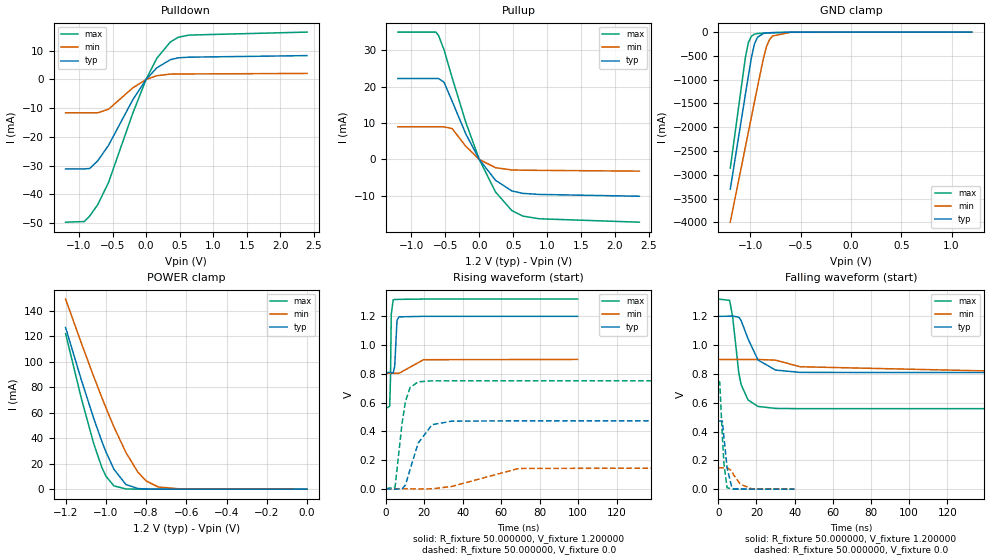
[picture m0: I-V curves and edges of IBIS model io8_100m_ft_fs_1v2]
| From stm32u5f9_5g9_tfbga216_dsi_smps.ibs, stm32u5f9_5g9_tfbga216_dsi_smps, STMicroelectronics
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|   Model io8_100m_ft_fs_1v2
[Model]  io8_100m_ft_fs_1v2
Model_type I/O
Polarity   Non-Inverting
Enable   Active-Low
Vinl =   0.360000V
Vinh =   0.840000V
Vmeas =  0.600000V
Cref =   50.000000pF
Rref =   100.000000M
Vref =   0.0V
C_comp   2.947800pF   2.877700pF   2.996100pF
[Temperature Range]   25.000000   0.140000k   -40.000000
[Pullup Reference]   1.200000V   0.900000V   1.320000V
[Pulldown Reference]   0.0V   0.0V   0.0V
[POWER Clamp Reference]   1.200000V   0.900000V   1.320000V
[GND Clamp Reference]   0.0V   0.0V   0.0V
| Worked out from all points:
|   slope of the pulldown table from 0 to 0.18 V, typ, clamps not added: 40.7 ohm
|   slope of the pullup table from 0 to 0.18 V, typ, clamps not added: 39.5 ohm
|   GND clamp passes 1 mA (typ) near -0.51 V on its own axis
|   POWER clamp passes 1 mA (typ) near -0.86 V on its own axis
|   rising waveform, R_fixture 50.000000, V_fixture 1.200000: 20-80 % time 753ps typ, 2.05ns min, 443ps max; typ from 0.809 V to 1.2 V
|   rising waveform, R_fixture 50.000000, V_fixture 0.0: 20-80 % time 7.25ns typ, 18.3ns min, 3.99ns max; typ from 0 V to 0.473 V
|   falling waveform, R_fixture 50.000000, V_fixture 1.200000: 20-80 % time 7.8ns typ, 18.5ns min, 4.53ns max; typ from 1.2 V to 0.809 V
|   falling waveform, R_fixture 50.000000, V_fixture 0.0: 20-80 % time 2.5ns typ, 4.76ns min, 1.85ns max; typ from 0.473 V to 0 V
[Pulldown]
|Voltage   I(typ)   I(min)   I(max)
-1.2V     -31.16mA   -11.61mA   -49.71mA
-920mV    -31.16mA   -11.61mA   -49.48mA
-840mV    -31mA      -11.61mA   -47.54mA
-720mV    -28.32mA   -11.61mA   -43.58mA
-560mV    -22.95mA   -10.37mA   -35.89mA
-200mV    -7.146mA   -2.964mA   -11.89mA
0V        0A         0A         0A
160mV     4.047mA    1.298mA    7.361mA
360mV     6.87mA     1.87mA     13mA
480mV     7.543mA    1.91mA     14.69mA
640mV     7.764mA    1.923mA    15.46mA
2.4V      8.308mA    2.101mA    16.5mA
[Pullup]
|Voltage   I(typ)   I(min)   I(max)
-1.2V     22.25mA    8.971mA    35.01mA
-640mV    22.25mA    8.971mA    35.01mA
-600mV    22.25mA    8.971mA    34.03mA
-520mV    21.23mA    8.971mA    30.12mA
-400mV    15.99mA    8.489mA    22.45mA
-200mV    7.069mA    3.642mA    10.26mA
0V        550fA      209pA      10fA
240mV     -5.73mA    -2.256mA   -8.953mA
480mV     -8.639mA   -2.877mA   -14.04mA
640mV     -9.31mA    -2.942mA   -15.55mA
880mV     -9.601mA   -2.986mA   -16.29mA
2.36V     -10.1mA    -3.2mA     -17.23mA
[GND_clamp]
|Voltage   I(typ)   I(min)   I(max)
-1.2V     -3.305A    -3.998A    -2.862A
-1.05V    -1.316A    -2.418A    -539.3mA
-1.02V    -921mA     -2.103A    -218.8mA
-990mV    -539.5mA   -1.788A    -87.43mA
-960mV    -252.1mA   -1.474A    -44.36mA
-930mV    -110.5mA   -1.16A     -30.32mA
-870mV    -28.03mA   -549.1mA   -21.09mA
-840mV    -18.43mA   -305.6mA   -18.27mA
-810mV    -13.9mA    -159.7mA   -15.73mA
-780mV    -11.23mA   -82.35mA   -13.37mA
-600mV    -2.976mA   -4.272mA   -3.058mA
1.2V      0A         14.74nA    0A
[POWER_clamp]
|Voltage   I(typ)   I(min)   I(max)
-1.2V     127mA      149.4mA    122.2mA
-1.12V    84.97mA    114mA      70.27mA
-1.06V    55.51mA    88.42mA    35.67mA
-1.02V    37.63mA    72.04mA    17.17mA
-1V       29.51mA    64.13mA    10.3mA
-960mV    15.69mA    48.99mA    2.571mA
-900mV    3.624mA    28.77mA    182.8uA
-840mV    490.7uA    13.24mA    11.35uA
-800mV    116.8uA    6.532mA    1.77uA
-740mV    13.2uA     1.723mA    109.1nA
-620mV    167.3nA    79.35uA    0A
0V        0A         17.84nA    0A
[Ramp]
| variable   typ   min   max
dV/dt_r  0.28375/7.23709n   88.91387m/18.29687n 0.45093/3.98287n
dV/dt_f  0.23460/7.79149n   57.88800m/18.44549n 0.45665/4.52035n
R_load = 50.000000
[Rising Waveform]
R_fixture= 50.000000
V_fixture= 1.200000
V_fixture_min= 0.900000
V_fixture_max= 1.320000
|time   V(typ)   V(min)   V(max)
0s        809mV      803.5mV    558.9mV
2.002ns   809mV      803.5mV    575mV
2.402ns   809.1mV    803.5mV    766.2mV
2.803ns   809mV      803.5mV    1.211V
3.804ns   804.9mV    803.5mV    1.315V
4.605ns   852.3mV    803.5mV    1.317V
5.806ns   1.173V     803.5mV    1.317V
6.807ns   1.196V     803.5mV    1.318V
19.62ns   1.2V       898.1mV    1.32V
99.7ns    1.2V       900mV      1.32V
[Rising Waveform]
R_fixture= 50.000000
V_fixture= 0.0
V_fixture_min= 0.0
V_fixture_max= 0.0
|time   V(typ)   V(min)   V(max)
0s        1.836uV    1.083uV    1.945uV
4.805ns   -2.478mV   913.4nV    12.59mV
8.408ns   -284.1uV   -121.6nV   453.8mV
10.21ns   26.6mV     1.793uV    609.6mV
12.61ns   136mV      48.02uV    704.5mV
16.82ns   318.1mV    -1.253mV   744.3mV
24.02ns   446.1mV    -17.07uV   751.1mV
34.23ns   470.7mV    16.32mV    751.4mV
69.07ns   472.8mV    141.6mV    751.5mV
299.1ns   472.9mV    148.2mV    751.5mV
[Falling Waveform]
R_fixture= 50.000000
V_fixture= 1.200000
V_fixture_min= 0.900000
V_fixture_max= 1.320000
|time   V(typ)   V(min)   V(max)
0s        1.2V       900mV      1.32V
6.006ns   1.201V     900.1mV    1.311V
7.608ns   1.202V     900.6mV    1.191V
10.81ns   1.194V     900.6mV    805mV
12.01ns   1.171V     900.5mV    726.7mV
15.62ns   1.044V     900.4mV    619.4mV
20.82ns   897.2mV    900.5mV    574.5mV
30.03ns   826.8mV    896mV      560.7mV
42.84ns   810.8mV    850mV      559mV
199.4ns   809mV      803.5mV    558.9mV
[Falling Waveform]
R_fixture= 50.000000
V_fixture= 0.0
V_fixture_min= 0.0
V_fixture_max= 0.0
|time   V(typ)   V(min)   V(max)
0s        472.9mV    148.2mV    751.5mV
800.8ps   472.9mV    148.3mV    743.2mV
2.162ns   473.5mV    148.3mV    371.3mV
3.043ns   357.3mV    148.2mV    172.6mV
4.645ns   150mV      148.4mV    10.1mV
6.887ns   23.41mV    129.9mV    1.826mV
8.168ns   2.679mV    97.71mV    920.1uV
11.61ns   1.107mV    34mV       296uV
17.38ns   297.1uV    2.863mV    67.68uV
39.88ns   1.836uV    1.083uV    1.945uV
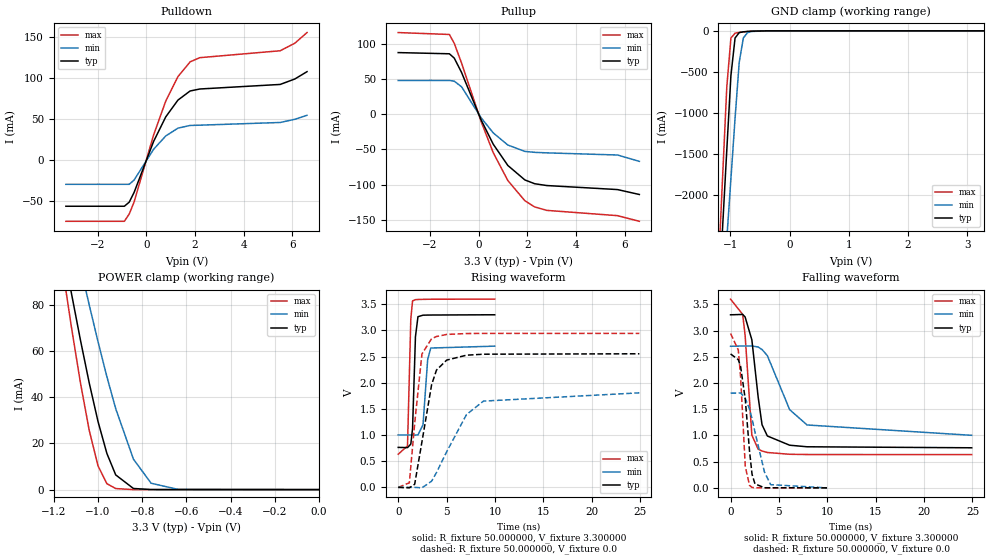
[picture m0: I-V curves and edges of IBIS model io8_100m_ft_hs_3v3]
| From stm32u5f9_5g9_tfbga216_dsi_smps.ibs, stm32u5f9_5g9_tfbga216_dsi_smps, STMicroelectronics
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|   Model io8_100m_ft_hs_3v3
[Model]  io8_100m_ft_hs_3v3
Model_type I/O
Polarity   Non-Inverting
Enable   Active-Low
Vinl =   0.990000V
Vinh =   2.310000V
Vmeas =  1.650000V
Cref =   50.000000pF
Rref =   100.000000M
Vref =   0.0V
C_comp   3.313100pF   3.281800pF   3.354500pF
[Temperature Range]   25.000000   0.140000k   -40.000000
[Pullup Reference]   3.300000V   2.700000V   3.600000V
[Pulldown Reference]   0.0V   0.0V   0.0V
[POWER Clamp Reference]   3.300000V   2.700000V   3.600000V
[GND Clamp Reference]   0.0V   0.0V   0.0V
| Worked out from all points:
|   slope of the pulldown table from 0 to 0.495 V, typ, clamps not added: 14 ohm
|   slope of the pullup table from 0 to 0.495 V, typ, clamps not added: 13.7 ohm
|   GND clamp passes 1 mA (typ) near -0.51 V on its own axis
|   POWER clamp passes 1 mA (typ) near -0.85 V on its own axis
|   rising waveform, R_fixture 50.000000, V_fixture 3.300000: 20-80 % time 245ps typ, 342ps min, 208ps max; typ from 0.764 V to 3.3 V
|   rising waveform, R_fixture 50.000000, V_fixture 0.0: 20-80 % time 1.41ns typ, 3.1ns min, 872ps max; typ from 0 V to 2.55 V
|   falling waveform, R_fixture 50.000000, V_fixture 3.300000: 20-80 % time 959ps typ, 2.51ns min, 626ps max; typ from 3.3 V to 0.764 V
|   falling waveform, R_fixture 50.000000, V_fixture 0.0: 20-80 % time 727ps typ, 1.36ns min, 504ps max; typ from 2.55 V to 0 V
[Pulldown]
|Voltage   I(typ)   I(min)   I(max)
-3.3V     -56.06mA   -29.42mA   -74.35mA
-900mV    -56.06mA   -29.42mA   -74.35mA
-700mV    -51.09mA   -29.42mA   -65.48mA
-500mV    -39.32mA   -24.2mA    -50.88mA
300mV     22.62mA    13.13mA    30.43mA
800mV     52.54mA    29.36mA    71.75mA
1.3V      72.91mA    38.82mA    101.4mA
1.8V      84.02mA    42.13mA    119.4mA
2.2V      86.43mA    42.46mA    124.5mA
5.5V      91.98mA    45.75mA    132.9mA
6.1V      98.6mA     49.6mA     142.1mA
6.6V      107.5mA    54.5mA     155mA
[Pullup]
|Voltage   I(typ)   I(min)   I(max)
-3.3V     87.21mA    47.72mA    115.6mA
-1.2V     85.52mA    47.72mA    112.9mA
-1V       79.41mA    46.66mA    100.4mA
-700mV    59.08mA    38.76mA    72.42mA
100mV     -8.009mA   -5.102mA   -10.2mA
600mV     -42.64mA   -26.6mA    -54.61mA
1.2V      -72.81mA   -43.84mA   -94.18mA
1.9V      -93.37mA   -52.9mA    -122.9mA
2.3V      -98.71mA   -54.23mA   -131.6mA
2.8V      -101.3mA   -54.97mA   -136.5mA
5.7V      -107mA     -58mA      -144mA
6.6V      -114mA     -67mA      -152mA
[GND_clamp]
|Voltage   I(typ)   I(min)   I(max)
-3.3V     -9.848A    -9.957A    -9.458A
-1.2V     -3.312A    -4.013A    -2.863A
-1.13V    -2.381A    -3.274A    -1.769A
-1.06V    -1.452A    -2.535A    -684.7mA
-990mV    -542.9mA   -1.798A    -88.02mA
-920mV    -87.11mA   -1.064A    -28.44mA
-850mV    -22.1mA    -382.4mA   -19.61mA
-780mV    -11.97mA   -86.98mA   -13.71mA
-710mV    -7.619mA   -22.26mA   -8.745mA
-640mV    -4.493mA   -7.773mA   -4.817mA
-360mV    -31.22uA   -172.6uA   -8.607uA
3.28V     0A         15.66nA    -5.841nA
[POWER_clamp]
|Voltage   I(typ)   I(min)   I(max)
-3.28V    1.355A     1.167A     1.664A
-1.16V    105.7mA    131.6mA    95.69mA
-1.12V    84.97mA    114mA      70.27mA
-1.08V    65.05mA    96.83mA    46.54mA
-1.04V    46.34mA    80.15mA    25.76mA
-1V       29.51mA    64.13mA    10.3mA
-960mV    15.69mA    48.99mA    2.571mA
-920mV    6.373mA    35.1mA     455.6uA
-840mV    490.7uA    13.24mA    11.36uA
-760mV    27.33uA    2.767mA    276.6nA
-640mV    346.6nA    134.1uA    15.62nA
0V        0A         19.91nA    0A
[Ramp]
| variable   typ   min   max
dV/dt_r  1.53252/1.41104n   1.08420/3.09938n   1.76664/0.87063n
dV/dt_f  1.52149/0.95635n   1.01802/2.50554n   1.77964/0.62432n
R_load = 50.000000
[Rising Waveform]
R_fixture= 50.000000
V_fixture= 3.300000
V_fixture_min= 2.700000
V_fixture_max= 3.600000
|time   V(typ)   V(min)   V(max)
0s        764.2mV    1.002V     633.9mV
961ps     760mV      1.002V     794mV
1.301ns   826.9mV    1.002V     3.216V
1.481ns   1.121V     1.002V     3.565V
1.782ns   2.884V     999.4mV    3.589V
2.042ns   3.263V     1.002V     3.592V
2.563ns   3.292V     1.198V     3.595V
3.043ns   3.294V     2.444V     3.596V
3.363ns   3.295V     2.664V     3.597V
9.97ns    3.3V       2.7V       3.599V
[Rising Waveform]
R_fixture= 50.000000
V_fixture= 0.0
V_fixture_min= 0.0
V_fixture_max= 0.0
|time   V(typ)   V(min)   V(max)
0s        6.7uV      6.794uV    3.582uV
1.151ns   -8.749mV   18.83uV    86.4mV
1.702ns   59.79mV    -904.3nV   1.225V
2.452ns   870.8mV    -9.576mV   2.551V
3.453ns   1.964V     118.8mV    2.843V
3.954ns   2.242V     282.3mV    2.884V
5.005ns   2.433V     679.4mV    2.924V
7.057ns   2.527V     1.392V     2.941V
8.809ns   2.546V     1.649V     2.944V
24.92ns   2.554V     1.807V     2.944V
[Falling Waveform]
R_fixture= 50.000000
V_fixture= 3.300000
V_fixture_min= 2.700000
V_fixture_max= 3.600000
|time   V(typ)   V(min)   V(max)
0s        3.3V       2.7V       3.599V
1.251ns   3.307V     2.705V     3.308V
1.502ns   3.26V      2.706V     2.919V
2.202ns   2.823V     2.706V     1.005V
2.853ns   1.732V     2.686V     738.5mV
3.253ns   1.204V     2.638V     702.6mV
3.804ns   989.2mV    2.522V     674.6mV
6.106ns   813.3mV    1.492V     640.4mV
7.908ns   783.5mV    1.199V     635.9mV
24.92ns   764.2mV    1.002V     633.9mV
[Falling Waveform]
R_fixture= 50.000000
V_fixture= 0.0
V_fixture_min= 0.0
V_fixture_max= 0.0
|time   V(typ)   V(min)   V(max)
0s        2.554V     1.807V     2.944V
800.8ps   2.444V     1.807V     2.63V
1.041ns   2.315V     1.811V     2.115V
1.522ns   1.687V     1.707V     408.1mV
1.962ns   699.7mV    1.505V     46.54mV
2.222ns   257.8mV    1.317V     7.735mV
2.523ns   75.89mV    1.064V     3.104mV
3.504ns   2.52mV     303mV      1.393mV
4.144ns   1.613mV    60.78mV    1.06mV
9.97ns    6.7uV      6.794uV    3.582uV
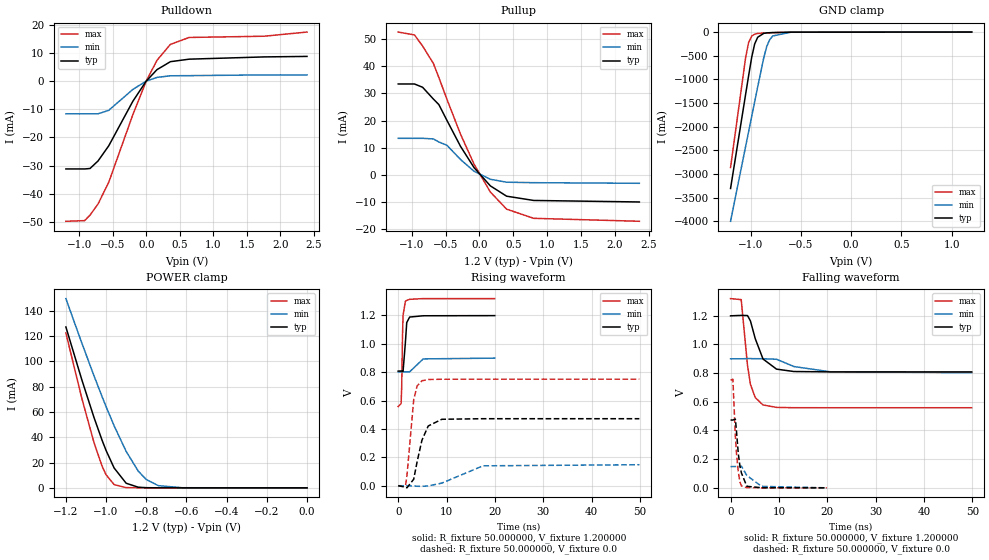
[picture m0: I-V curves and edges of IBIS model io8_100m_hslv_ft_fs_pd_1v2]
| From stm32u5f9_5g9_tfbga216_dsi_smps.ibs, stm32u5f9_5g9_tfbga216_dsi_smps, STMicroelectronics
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|   Model io8_100m_hslv_ft_fs_pd_1v2
[Model]  io8_100m_hslv_ft_fs_pd_1v2
Model_type I/O
Polarity   Non-Inverting
Enable   Active-Low
Vinl =   0.360000V
Vinh =   0.840000V
Vmeas =  0.600000V
Cref =   50.000000pF
Rref =   100.000000M
Vref =   0.0V
C_comp   3.030100pF   2.960800pF   3.078300pF
[Temperature Range]   25.000000   0.140000k   -40.000000
[Pullup Reference]   1.200000V   0.900000V   1.320000V
[Pulldown Reference]   0.0V   0.0V   0.0V
[POWER Clamp Reference]   1.200000V   0.900000V   1.320000V
[GND Clamp Reference]   0.0V   0.0V   0.0V
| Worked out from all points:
|   slope of the pulldown table from 0 to 0.18 V, typ, clamps not added: 40.7 ohm
|   slope of the pullup table from 0 to 0.18 V, typ, clamps not added: 39.5 ohm
|   GND clamp passes 1 mA (typ) near -0.51 V on its own axis
|   POWER clamp passes 1 mA (typ) near -0.86 V on its own axis
|   rising waveform, R_fixture 50.000000, V_fixture 1.200000: 20-80 % time 362ps typ, 843ps min, 238ps max; typ from 0.808 V to 1.2 V
|   rising waveform, R_fixture 50.000000, V_fixture 0.0: 20-80 % time 2ns typ, 4.56ns min, 1.18ns max; typ from 0 V to 0.472 V
|   falling waveform, R_fixture 50.000000, V_fixture 1.200000: 20-80 % time 2.46ns typ, 5.4ns min, 1.5ns max; typ from 1.2 V to 0.808 V
|   falling waveform, R_fixture 50.000000, V_fixture 0.0: 20-80 % time 1.05ns typ, 1.99ns min, 804ps max; typ from 0.472 V to 0 V
[Pulldown]
|Voltage   I(typ)   I(min)   I(max)
-1.2V     -31.16mA   -11.61mA   -49.71mA
-920mV    -31.16mA   -11.61mA   -49.48mA
-840mV    -31mA      -11.61mA   -47.54mA
-720mV    -28.33mA   -11.61mA   -43.58mA
-560mV    -22.95mA   -10.37mA   -35.89mA
-200mV    -7.146mA   -2.964mA   -11.89mA
0V        0A         -1pA       0A
160mV     4.047mA    1.298mA    7.361mA
360mV     6.87mA     1.87mA     13mA
640mV     7.765mA    1.923mA    15.46mA
1.76V     8.564mA    2.187mA    15.9mA
2.4V      8.742mA    2.187mA    17.38mA
[Pullup]
|Voltage   I(typ)   I(min)   I(max)
-1.2V     33.49mA    13.42mA    52.68mA
-960mV    33.49mA    13.42mA    51.61mA
-840mV    32.28mA    13.42mA    47.51mA
-680mV    27.9mA     13.19mA    41.05mA
-600mV    25.88mA    12.07mA    35.87mA
-480mV    20.01mA    10.83mA    27.79mA
-280mV    10.44mA    5.592mA    14.93mA
-80mV     2.58mA     1.232mA    3.849mA
160mV     -4.145mA   -1.713mA   -6.415mA
400mV     -7.962mA   -2.792mA   -12.75mA
800mV     -9.537mA   -2.973mA   -16.14mA
2.36V     -10.1mA    -3.2mA     -17.23mA
[GND_clamp]
|Voltage   I(typ)   I(min)   I(max)
-1.2V     -3.305A    -3.998A    -2.862A
-1.05V    -1.316A    -2.418A    -539.3mA
-1.02V    -921mA     -2.103A    -218.8mA
-990mV    -539.5mA   -1.788A    -87.45mA
-960mV    -252.2mA   -1.474A    -44.37mA
-930mV    -110.5mA   -1.16A     -30.33mA
-870mV    -28.04mA   -549.1mA   -21.1mA
-840mV    -18.44mA   -305.6mA   -18.29mA
-810mV    -13.92mA   -159.7mA   -15.75mA
-780mV    -11.24mA   -82.36mA   -13.39mA
-600mV    -2.986mA   -4.279mA   -3.072mA
1.2V      30.28uA    18.17uA    37.27uA
[POWER_clamp]
|Voltage   I(typ)   I(min)   I(max)
-1.2V     127mA      149.4mA    122.2mA
-1.12V    84.97mA    114mA      70.27mA
-1.06V    55.51mA    88.42mA    35.67mA
-1.02V    37.63mA    72.04mA    17.17mA
-1V       29.51mA    64.13mA    10.3mA
-960mV    15.69mA    48.99mA    2.571mA
-900mV    3.624mA    28.77mA    182.8uA
-840mV    490.7uA    13.24mA    11.35uA
-800mV    116.8uA    6.532mA    1.77uA
-740mV    13.2uA     1.723mA    109.1nA
-620mV    167.3nA    79.35uA    0A
0V        0A         17.84nA    0A
[Ramp]
| variable   typ   min   max
dV/dt_r  0.28340/1.99687n   88.81788m/4.55262n  0.45044/1.18302n
dV/dt_f  0.23486/2.45404n   58.02600m/5.39175n  0.45673/1.50145n
R_load = 50.000000
[Rising Waveform]
R_fixture= 50.000000
V_fixture= 1.200000
V_fixture_min= 0.900000
V_fixture_max= 1.320000
|time   V(typ)   V(min)   V(max)
0s        808mV      802.7mV    558.3mV
600.6ps   808.7mV    802.7mV    579.2mV
720.7ps   808.6mV    802.7mV    698.5mV
880.9ps   807.1mV    802.7mV    1.046V
1.001ns   805.7mV    802.7mV    1.2V
1.481ns   1.009V     802.8mV    1.3V
1.762ns   1.15V      802.9mV    1.306V
2.362ns   1.189V     802.9mV    1.314V
5.165ns   1.198V     893.9mV    1.319V
19.94ns   1.199V     899.4mV    1.319V
[Rising Waveform]
R_fixture= 50.000000
V_fixture= 0.0
V_fixture_min= 0.0
V_fixture_max= 0.0
|time   V(typ)   V(min)   V(max)
0s        -14.66uV   -6.095uV   -48.72uV
1.502ns   -10.14mV   -40.81uV   -1.013mV
1.802ns   -14.87mV   -38.25uV   69.37mV
3.203ns   45.81mV    -1.916mV   606.2mV
3.904ns   168.6mV    -3.803mV   703mV
4.905ns   320.8mV    -4.272mV   740mV
6.206ns   421.2mV    -1.571mV   748.8mV
9.009ns   468.4mV    18.4mV     750.7mV
17.52ns   472.4mV    140.2mV    750.9mV
49.85ns   472.4mV    148.1mV    750.9mV
[Falling Waveform]
R_fixture= 50.000000
V_fixture= 1.200000
V_fixture_min= 0.900000
V_fixture_max= 1.320000
|time   V(typ)   V(min)   V(max)
0s        1.199V     899.4mV    1.319V
2.202ns   1.202V     899.1mV    1.312V
3.504ns   1.201V     901.4mV    854.4mV
4.104ns   1.164V     900.9mV    721.7mV
5.105ns   1.04V      900.1mV    629.1mV
6.707ns   898.1mV    899.9mV    577.7mV
9.51ns    827.3mV    896.3mV    560.7mV
13.11ns   810.7mV    845.4mV    558.5mV
20.62ns   808.1mV    808.8mV    558.3mV
49.85ns   808mV      802.7mV    558.3mV
[Falling Waveform]
R_fixture= 50.000000
V_fixture= 0.0
V_fixture_min= 0.0
V_fixture_max= 0.0
|time   V(typ)   V(min)   V(max)
0s        472.4mV    148.1mV    750.9mV
480.5ps   472.6mV    148.2mV    756.6mV
1.001ns   478.8mV    148.2mV    357.1mV
1.241ns   388.5mV    148.2mV    234.3mV
1.602ns   237.5mV    148.1mV    114mV
1.922ns   156.2mV    148.4mV    42.56mV
2.242ns   104.2mV    151.4mV    12.92mV
3.363ns   10.66mV    86.08mV    1.68mV
6.406ns   686.2uV    10.19mV    72.86uV
19.94ns   -14.66uV   -6.095uV   -48.72uV
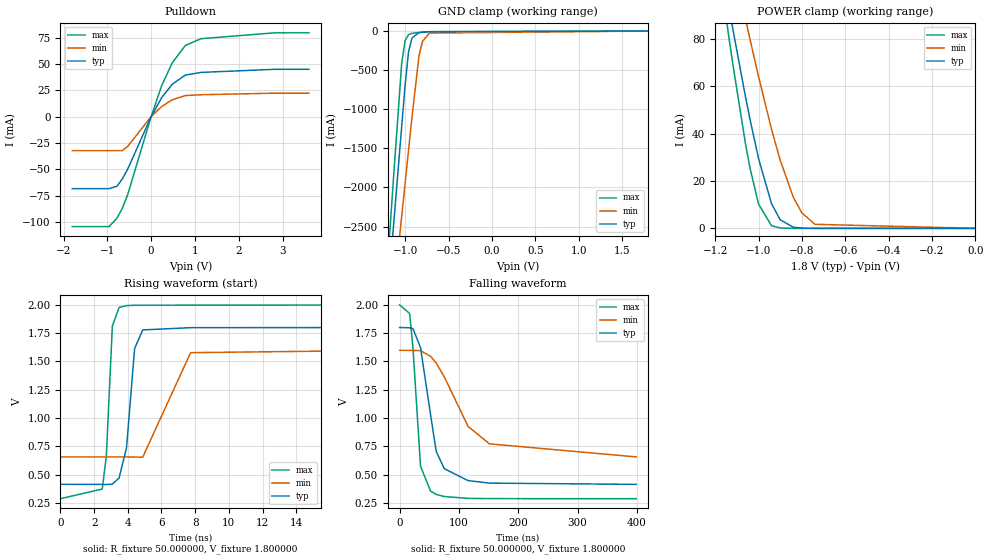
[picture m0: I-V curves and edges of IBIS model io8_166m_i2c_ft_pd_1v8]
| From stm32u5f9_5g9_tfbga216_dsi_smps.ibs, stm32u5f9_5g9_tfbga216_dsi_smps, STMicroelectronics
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|   Model io8_166m_i2c_ft_pd_1v8
[Model]  io8_166m_i2c_ft_pd_1v8
Model_type I/O_open_drain
Polarity   Non-Inverting
Enable   Active-Low
Vinl =   0.540000V
Vinh =   1.260000V
Vmeas =  0.800000V
Cref =   50.000000pF
Rref =   10.000000
Vref =   0.900000V
C_comp   3.364500pF   3.359200pF   3.406800pF
[Temperature Range]   25.000000   0.140000k   -40.000000
[Pullup Reference]   1.800000V   1.600000V   2.000000V
[Pulldown Reference]   0.0V   0.0V   0.0V
[POWER Clamp Reference]   1.800000V   1.600000V   2.000000V
[GND Clamp Reference]   0.0V   0.0V   0.0V
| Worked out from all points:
|   slope of the pulldown table from 0 to 0.27 V, typ, clamps not added: 13.6 ohm
|   GND clamp passes 1 mA (typ) near -0.50 V on its own axis
|   POWER clamp passes 1 mA (typ) near -0.86 V on its own axis
|   rising waveform, R_fixture 50.000000, V_fixture 1.800000: 20-80 % time 442ps typ, 899ps min, 293ps max; typ from 0.414 V to 1.8 V
|   falling waveform, R_fixture 50.000000, V_fixture 1.800000: 20-80 % time 23.4ns typ, 59.2ns min, 12.2ns max; typ from 1.8 V to 0.414 V
[Pulldown]
|Voltage   I(typ)   I(min)   I(max)
-1.8V     -68.38mA   -32.32mA   -104.4mA
-960mV    -68.38mA   -32.32mA   -104.4mA
-780mV    -66.08mA   -32.32mA   -96.43mA
-660mV    -59.2mA    -32.31mA   -87.22mA
-540mV    -50.22mA   -28.51mA   -74.66mA
0V        -10fA      -200fA     0A
240mV     18.04mA    9.6mA      29.42mA
480mV     30.68mA    16.02mA    50.95mA
780mV     39.48mA    19.99mA    67.56mA
1.14V     41.99mA    20.78mA    74.01mA
2.82V     44.93mA    22.28mA    79.57mA
3.6V      44.93mA    22.28mA    79.57mA
[GND_clamp]
|Voltage   I(typ)   I(min)   I(max)
-1.8V     -9.908A    -9.683A    -9.994A
-1.2V     -3.383A    -4.084A    -2.934A
-1.16V    -2.841A    -3.655A    -2.294A
-1.12V    -2.299A    -3.226A    -1.656A
-1.04V    -1.218A    -2.369A    -414.2mA
-1V       -684.7mA   -1.941A    -119.2mA
-960mV    -257.2mA   -1.514A    -45.67mA
-920mV    -87.04mA   -1.089A    -28.94mA
-840mV    -19.36mA   -312.8mA   -18.98mA
-800mV    -13.56mA   -132.4mA   -15.51mA
-720mV    -8.053mA   -25.67mA   -9.505mA
1.8V      45.71uA    33.32uA    56.11uA
[POWER_clamp]
|Voltage   I(typ)   I(min)   I(max)
-1.8V     470.8mA    433.7mA    554.6mA
-1.14V    95.25mA    122.7mA    82.82mA
-1.12V    84.97mA    114mA      70.27mA
-1.06V    55.51mA    88.42mA    35.67mA
-1.04V    46.34mA    80.15mA    25.76mA
-1V       29.51mA    64.13mA    10.3mA
-940mV    10.39mA    41.86mA    1.109mA
-900mV    3.624mA    28.77mA    182.8uA
-840mV    490.7uA    13.24mA    11.35uA
-800mV    116.8uA    6.532mA    1.77uA
-740mV    13.2uA     1.724mA    109.3nA
0V        0A         18.75nA    0A
[Ramp]
| variable   typ   min   max
dV/dt_r  0.83119/0.44455n   0.56525/0.89877n   1.02738/0.29256n
dV/dt_f  0.83143/23.37507n   0.56491/59.21208n   1.02744/12.19581n
R_load = 50.000000
[Rising Waveform]
R_fixture= 50.000000
V_fixture= 1.800000
V_fixture_min= 1.600000
V_fixture_max= 2.000000
|time   V(typ)   V(min)   V(max)
0s        413.8mV    656.4mV    287.1mV
2.482ns   413.5mV    656.4mV    372.3mV
2.723ns   412.6mV    656.4mV    660.2mV
3.083ns   416.1mV    656.4mV    1.814V
3.483ns   470.5mV    656.4mV    1.978V
3.924ns   738.4mV    656.3mV    1.994V
4.404ns   1.614V     655.3mV    1.997V
4.885ns   1.779V     653.9mV    1.997V
7.728ns   1.799V     1.578V     1.998V
19.94ns   1.8V       1.599V     2V
[Falling Waveform]
R_fixture= 50.000000
V_fixture= 1.800000
V_fixture_min= 1.600000
V_fixture_max= 2.000000
|time   V(typ)   V(min)   V(max)
0s        1.8V       1.599V     2V
16.82ns   1.798V     1.598V     1.925V
22.42ns   1.791V     1.598V     1.623V
35.24ns   1.622V     1.595V     574.5mV
52.05ns   1.032V     1.546V     353.8mV
61.66ns   704.5mV    1.486V     325mV
75.28ns   552.5mV    1.364V     306.1mV
115.3ns   446.9mV    926.3mV    290mV
151.4ns   424.8mV    772mV      287.7mV
398.8ns   413.8mV    656.4mV    287.1mV
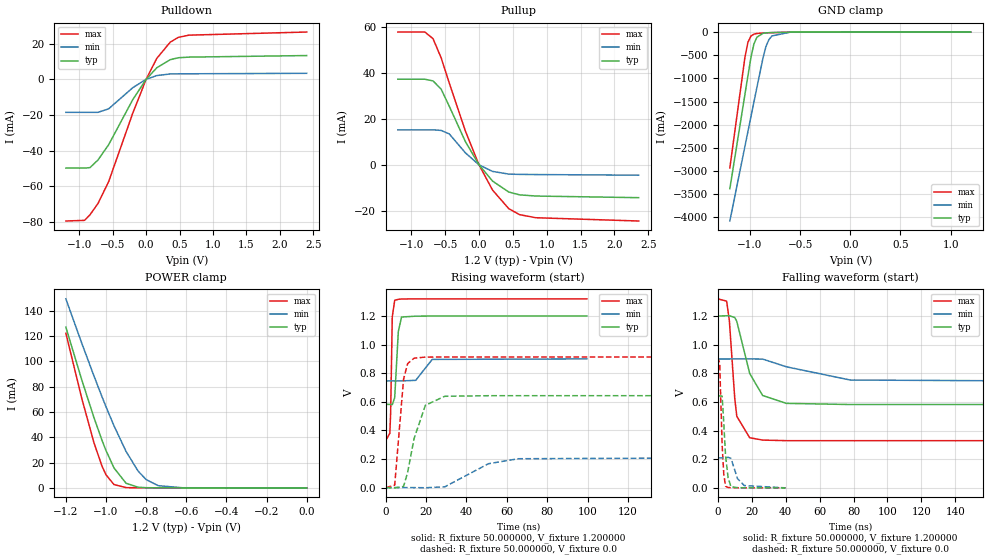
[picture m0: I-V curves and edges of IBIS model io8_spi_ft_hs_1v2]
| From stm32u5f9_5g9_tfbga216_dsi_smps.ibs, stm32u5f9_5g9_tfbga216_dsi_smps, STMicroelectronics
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|   Model io8_spi_ft_hs_1v2
[Model]  io8_spi_ft_hs_1v2
Model_type I/O
Polarity   Non-Inverting
Enable   Active-Low
Vinl =   0.360000V
Vinh =   0.840000V
Vmeas =  0.600000V
Cref =   50.000000pF
Rref =   100.000000M
Vref =   0.0V
C_comp   3.132800pF   3.069700pF   3.178000pF
[Temperature Range]   25.000000   0.140000k   -40.000000
[Pullup Reference]   1.200000V   0.900000V   1.320000V
[Pulldown Reference]   0.0V   0.0V   0.0V
[POWER Clamp Reference]   1.200000V   0.900000V   1.320000V
[GND Clamp Reference]   0.0V   0.0V   0.0V
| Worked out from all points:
|   slope of the pulldown table from 0 to 0.18 V, typ, clamps not added: 25.4 ohm
|   slope of the pullup table from 0 to 0.18 V, typ, clamps not added: 27.8 ohm
|   GND clamp passes 1 mA (typ) near -0.51 V on its own axis
|   POWER clamp passes 1 mA (typ) near -0.86 V on its own axis
|   rising waveform, R_fixture 50.000000, V_fixture 1.200000: 20-80 % time 1.31ns typ, 3.47ns min, 671ps max; typ from 0.582 V to 1.2 V
|   rising waveform, R_fixture 50.000000, V_fixture 0.0: 20-80 % time 6.24ns typ, 16ns min, 3.02ns max; typ from 0 V to 0.643 V
|   falling waveform, R_fixture 50.000000, V_fixture 1.200000: 20-80 % time 8.69ns typ, 20.8ns min, 3.7ns max; typ from 1.2 V to 0.582 V
|   falling waveform, R_fixture 50.000000, V_fixture 0.0: 20-80 % time 2.1ns typ, 4.02ns min, 1.52ns max; typ from 0.643 V to 0 V
[Pulldown]
|Voltage   I(typ)   I(min)   I(max)
-1.2V     -49.85mA   -18.57mA   -79.56mA
-920mV    -49.85mA   -18.57mA   -79.19mA
-840mV    -49.59mA   -18.57mA   -76.08mA
-720mV    -45.32mA   -18.57mA   -69.74mA
-560mV    -36.71mA   -16.58mA   -57.44mA
-200mV    -11.43mA   -4.74mA    -19.03mA
0V        0A         -600fA     0A
160mV     6.476mA    2.075mA    11.78mA
360mV     10.99mA    2.989mA    20.81mA
480mV     12.07mA    3.053mA    23.52mA
640mV     12.43mA    3.074mA    24.76mA
2.4V      13.31mA    3.34mA     26.51mA
[Pullup]
|Voltage   I(typ)   I(min)   I(max)
-1.2V     37.31mA    15.26mA    57.88mA
-800mV    37.31mA    15.26mA    57.88mA
-680mV    36.58mA    15.26mA    54.98mA
-560mV    33mA       15mA       46.63mA
-440mV    25.52mA    13.49mA    35.67mA
-200mV    10.05mA    5.175mA    14.59mA
0V        580fA      233pA      0A
200mV     -7.072mA   -2.852mA   -11mA
440mV     -11.84mA   -4.03mA    -19.1mA
600mV     -13.07mA   -4.154mA   -21.71mA
840mV     -13.59mA   -4.223mA   -23.04mA
2.36V     -14.3mA    -4.5mA     -24.47mA
[GND_clamp]
|Voltage   I(typ)   I(min)   I(max)
-1.2V     -3.379A    -4.076A    -2.932A
-1.05V    -1.35A     -2.47A     -550.7mA
-1.02V    -947.8mA   -2.149A    -221.5mA
-990mV    -552.4mA   -1.829A    -88.44mA
-960mV    -255.3mA   -1.51A     -44.87mA
-930mV    -111.8mA   -1.191A    -30.68mA
-870mV    -28.35mA   -564.6mA   -21.34mA
-840mV    -18.65mA   -309.5mA   -18.49mA
-810mV    -14.07mA   -161.6mA   -15.92mA
-780mV    -11.37mA   -83.33mA   -13.53mA
-600mV    -3.009mA   -4.321mA   -3.091mA
1.2V      0A         13.65nA    0A
[POWER_clamp]
|Voltage   I(typ)   I(min)   I(max)
-1.2V     127mA      149.4mA    122.2mA
-1.12V    84.97mA    114mA      70.27mA
-1.06V    55.51mA    88.42mA    35.67mA
-1.02V    37.63mA    72.04mA    17.17mA
-1V       29.51mA    64.13mA    10.3mA
-960mV    15.69mA    48.99mA    2.571mA
-900mV    3.624mA    28.77mA    182.8uA
-840mV    490.7uA    13.24mA    11.35uA
-800mV    116.8uA    6.532mA    1.77uA
-740mV    13.2uA     1.724mA    109.1nA
-620mV    167.4nA    79.36uA    0A
0V        0A         17.87nA    0A
[Ramp]
| variable   typ   min   max
dV/dt_r  0.38564/6.23137n   0.12553/15.91315n   0.54826/3.00577n
dV/dt_f  0.37078/8.68374n   92.42400m/20.74691n 0.59435/3.69688n
R_load = 50.000000
[Rising Waveform]
R_fixture= 50.000000
V_fixture= 1.200000
V_fixture_min= 0.900000
V_fixture_max= 1.320000
|time   V(typ)   V(min)   V(max)
0s        582mV      745.9mV    329.4mV
2.002ns   582.1mV    745.9mV    380.1mV
2.402ns   582mV      745.9mV    525.4mV
3.203ns   580mV      745.9mV    1.194V
4.404ns   629mV      745.9mV    1.31V
6.206ns   1.092V     745.9mV    1.317V
7.808ns   1.193V     746mV      1.319V
14.81ns   1.199V     750.1mV    1.32V
23.02ns   1.2V       896.6mV    1.32V
99.7ns    1.2V       900mV      1.32V
[Rising Waveform]
R_fixture= 50.000000
V_fixture= 0.0
V_fixture_min= 0.0
V_fixture_max= 0.0
|time   V(typ)   V(min)   V(max)
0s        1.319uV    949.7nV    109.5nV
4.404ns   -1.865mV   785.3nV    16.67mV
8.809ns   8.008mV    -251nV     759mV
10.81ns   106mV      8.805uV    866.9mV
14.01ns   342.6mV    -142uV     905.1mV
19.62ns   575.8mV    -1.182mV   912.8mV
29.23ns   638.6mV    5.363mV    913.4mV
50.85ns   642.6mV    166.8mV    913.5mV
65.67ns   642.7mV    201.8mV    913.5mV
199.4ns   642.8mV    209.3mV    913.5mV
[Falling Waveform]
R_fixture= 50.000000
V_fixture= 1.200000
V_fixture_min= 0.900000
V_fixture_max= 1.320000
|time   V(typ)   V(min)   V(max)
0s        1.2V       900mV      1.32V
5.205ns   1.202V     899.9mV    1.304V
6.807ns   1.202V     900mV      1.169V
10.01ns   1.19V      901.1mV    621.9mV
11.21ns   1.162V     901.1mV    499.9mV
18.82ns   798.4mV    900.6mV    349.9mV
26.43ns   645.1mV    899.5mV    333.6mV
40.44ns   590mV      845.4mV    329.6mV
78.08ns   582mV      753.1mV    329.4mV
199.4ns   582mV      745.9mV    329.4mV
[Falling Waveform]
R_fixture= 50.000000
V_fixture= 0.0
V_fixture_min= 0.0
V_fixture_max= 0.0
|time   V(typ)   V(min)   V(max)
0s        642.8mV    209.3mV    913.5mV
1.121ns   642.3mV    209.3mV    869.7mV
2.563ns   640.9mV    209.3mV    297.5mV
3.524ns   453.4mV    209.2mV    96.43mV
4.565ns   225.3mV    209.2mV    11.01mV
6.086ns   71.09mV    213.4mV    2.796mV
7.768ns   7.453mV    205.7mV    1.13mV
11.61ns   1.364mV    64.5mV     325.1uV
15.62ns   508.1uV    16mV       130.2uV
39.88ns   1.319uV    949.7nV    109.5nV
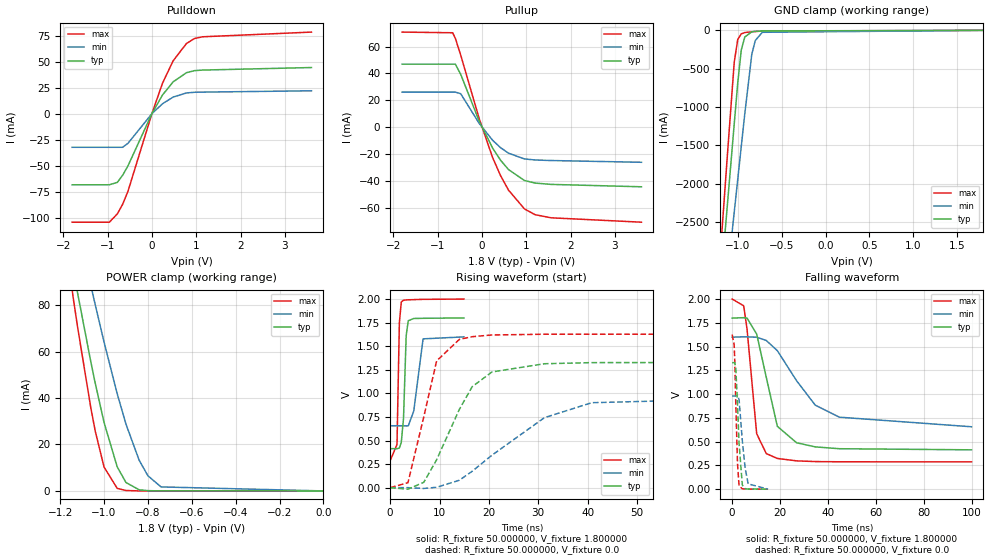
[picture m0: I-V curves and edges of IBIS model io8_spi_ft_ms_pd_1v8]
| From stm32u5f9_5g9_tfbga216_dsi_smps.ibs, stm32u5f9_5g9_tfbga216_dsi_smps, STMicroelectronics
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|   Model io8_spi_ft_ms_pd_1v8
[Model]  io8_spi_ft_ms_pd_1v8
Model_type I/O
Polarity   Non-Inverting
Enable   Active-Low
Vinl =   0.540000V
Vinh =   1.260000V
Vmeas =  0.900000V
Cref =   50.000000pF
Rref =   100.000000M
Vref =   0.0V
C_comp   3.338500pF   3.332300pF   3.378900pF
[Temperature Range]   25.000000   0.140000k   -40.000000
[Pullup Reference]   1.800000V   1.600000V   2.000000V
[Pulldown Reference]   0.0V   0.0V   0.0V
[POWER Clamp Reference]   1.800000V   1.600000V   2.000000V
[GND Clamp Reference]   0.0V   0.0V   0.0V
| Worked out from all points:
|   slope of the pulldown table from 0 to 0.27 V, typ, clamps not added: 13.6 ohm
|   slope of the pullup table from 0 to 0.27 V, typ, clamps not added: 15.9 ohm
|   GND clamp passes 1 mA (typ) near -0.50 V on its own axis
|   POWER clamp passes 1 mA (typ) near -0.86 V on its own axis
|   rising waveform, R_fixture 50.000000, V_fixture 1.800000: 20-80 % time 497ps typ, 1.03ns min, 320ps max; typ from 0.414 V to 1.8 V
|   rising waveform, R_fixture 50.000000, V_fixture 0.0: 20-80 % time 7.37ns typ, 15.8ns min, 4.01ns max; typ from 0 V to 1.33 V
|   falling waveform, R_fixture 50.000000, V_fixture 1.800000: 20-80 % time 6.93ns typ, 16.6ns min, 3.65ns max; typ from 1.8 V to 0.414 V
|   falling waveform, R_fixture 50.000000, V_fixture 0.0: 20-80 % time 1.4ns typ, 2.06ns min, 1.01ns max; typ from 1.33 V to 0 V
[Pulldown]
|Voltage   I(typ)   I(min)   I(max)
-1.8V     -68.38mA   -32.32mA   -104.4mA
-960mV    -68.38mA   -32.32mA   -104.4mA
-780mV    -66.07mA   -32.32mA   -96.42mA
-660mV    -59.2mA    -32.31mA   -87.22mA
-540mV    -50.22mA   -28.51mA   -74.66mA
0V        -10fA      -300fA     0A
240mV     18.04mA    9.599mA    29.41mA
480mV     30.68mA    16.02mA    50.95mA
780mV     39.47mA    19.98mA    67.56mA
960mV     41.44mA    20.62mA    72.37mA
1.14V     41.99mA    20.78mA    74.01mA
3.6V      44.44mA    22.06mA    78.55mA
[Pullup]
|Voltage   I(typ)   I(min)   I(max)
-1.8V     46.9mA     26.15mA    70.72mA
-660mV    46.9mA     26.15mA    70.22mA
-600mV    46.9mA     26.15mA    66.12mA
-480mV    39.44mA    24.97mA    53.77mA
-60mV     4.42mA     2.808mA    6.308mA
240mV     -15.38mA   -9.6mA     -22.37mA
420mV     -24.43mA   -15.12mA   -35.87mA
600mV     -31.41mA   -19.24mA   -46.67mA
960mV     -39.54mA   -23.52mA   -60.64mA
1.2V      -41.44mA   -24.28mA   -64.93mA
1.56V     -42.42mA   -24.69mA   -67.24mA
3.6V      -44.2mA    -26mA      -70.5mA
[GND_clamp]
|Voltage   I(typ)   I(min)   I(max)
-1.8V     -9.908A    -9.683A    -9.994A
-1.2V     -3.383A    -4.084A    -2.934A
-1.16V    -2.841A    -3.655A    -2.294A
-1.12V    -2.299A    -3.226A    -1.656A
-1.04V    -1.218A    -2.369A    -414.2mA
-1V       -684.7mA   -1.941A    -119.2mA
-960mV    -257.2mA   -1.514A    -45.67mA
-920mV    -87.04mA   -1.089A    -28.94mA
-840mV    -19.36mA   -312.8mA   -18.98mA
-800mV    -13.56mA   -132.4mA   -15.51mA
-720mV    -8.053mA   -25.67mA   -9.504mA
1.8V      45.71uA    33.32uA    56.11uA
[POWER_clamp]
|Voltage   I(typ)   I(min)   I(max)
-1.8V     470.8mA    433.7mA    554.6mA
-1.14V    95.25mA    122.7mA    82.82mA
-1.12V    84.97mA    114mA      70.27mA
-1.06V    55.51mA    88.42mA    35.67mA
-1.04V    46.34mA    80.15mA    25.76mA
-1V       29.51mA    64.13mA    10.3mA
-940mV    10.39mA    41.86mA    1.109mA
-900mV    3.624mA    28.77mA    182.8uA
-840mV    490.7uA    13.24mA    11.35uA
-800mV    116.8uA    6.532mA    1.77uA
-740mV    13.2uA     1.724mA    109.3nA
0V        0A         18.75nA    0A
[Ramp]
| variable   typ   min   max
dV/dt_r  0.79740/7.35500n   0.58765/15.72542n   0.97632/4.00122n
dV/dt_f  0.83140/6.91682n   0.56362/16.53379n   1.02743/3.64305n
R_load = 50.000000
[Rising Waveform]
R_fixture= 50.000000
V_fixture= 1.800000
V_fixture_min= 1.600000
V_fixture_max= 2.000000
|time   V(typ)   V(min)   V(max)
0s        413.8mV    656.5mV    287.1mV
1.381ns   412.9mV    656.5mV    456.7mV
1.862ns   420.7mV    656.5mV    1.748V
2.252ns   481.2mV    656.5mV    1.968V
2.703ns   735.6mV    656.2mV    1.988V
3.243ns   1.613V     654.7mV    1.991V
3.664ns   1.77V      655.2mV    1.992V
4.775ns   1.794V     812.1mV    1.994V
6.667ns   1.796V     1.578V     1.997V
14.95ns   1.8V       1.599V     2V
[Rising Waveform]
R_fixture= 50.000000
V_fixture= 0.0
V_fixture_min= 0.0
V_fixture_max= 0.0
|time   V(typ)   V(min)   V(max)
0s        2.121uV    2.362uV    111.7nV
3.604ns   -16.08mV   -99.25uV   52.71mV
6.807ns   56.47mV    -8.502mV   750.6mV
9.409ns   295.2mV    3.691mV    1.344V
14.01ns   829.5mV    78.61mV    1.572V
16.62ns   1.071V     173.8mV    1.601V
20.62ns   1.227V     344.2mV    1.619V
31.23ns   1.314V     741.6mV    1.627V
40.84ns   1.326V     900.9mV    1.627V
99.7ns    1.329V     979.8mV    1.627V
[Falling Waveform]
R_fixture= 50.000000
V_fixture= 1.800000
V_fixture_min= 1.600000
V_fixture_max= 2.000000
|time   V(typ)   V(min)   V(max)
0s        1.8V       1.599V     2V
4.805ns   1.804V     1.603V     1.929V
6.206ns   1.799V     1.602V     1.682V
10.21ns   1.632V     1.599V     583.4mV
14.21ns   1.176V     1.564V     374.5mV
18.82ns   661.3mV    1.457V     323.1mV
26.83ns   488.2mV    1.141V     297.7mV
34.63ns   444.8mV    883.4mV    290.3mV
44.64ns   425.5mV    757.4mV    288mV
99.7ns    413.8mV    656.5mV    287.1mV
[Falling Waveform]
R_fixture= 50.000000
V_fixture= 0.0
V_fixture_min= 0.0
V_fixture_max= 0.0
|time   V(typ)   V(min)   V(max)
0s        1.329V     979.8mV    1.627V
810.8ps   1.332V     979.8mV    1.524V
1.051ns   1.335V     979.8mV    1.375V
1.532ns   1.264V     979.6mV    877.8mV
2.222ns   896.1mV    987mV      270.9mV
2.883ns   478.2mV    942.2mV    32.18mV
4.234ns   42.91mV    508mV      4.04mV
5.405ns   3.671mV    221.6mV    2.528mV
6.667ns   1.793mV    55.57mV    1.287mV
14.95ns   2.121uV    2.362uV    111.7nV
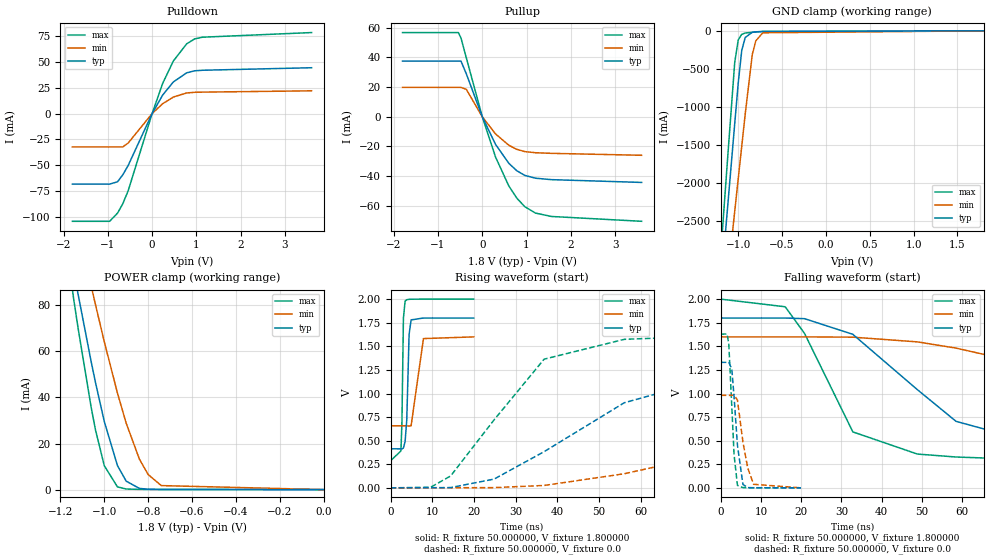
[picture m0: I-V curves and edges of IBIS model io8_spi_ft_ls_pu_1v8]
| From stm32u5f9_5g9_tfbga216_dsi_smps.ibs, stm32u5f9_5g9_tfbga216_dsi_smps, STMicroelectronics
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|   Model io8_spi_ft_ls_pu_1v8
[Model]  io8_spi_ft_ls_pu_1v8
Model_type I/O
Polarity   Non-Inverting
Enable   Active-Low
Vinl =   0.540000V
Vinh =   1.260000V
Vmeas =  0.900000V
Cref =   50.000000pF
Rref =   100.000000M
Vref =   0.0V
C_comp   3.338500pF   3.332300pF   3.378900pF
[Temperature Range]   25.000000   0.140000k   -40.000000
[Pullup Reference]   1.800000V   1.600000V   2.000000V
[Pulldown Reference]   0.0V   0.0V   0.0V
[POWER Clamp Reference]   1.800000V   1.600000V   2.000000V
[GND Clamp Reference]   0.0V   0.0V   0.0V
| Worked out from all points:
|   slope of the pulldown table from 0 to 0.27 V, typ, clamps not added: 13.6 ohm
|   slope of the pullup table from 0 to 0.27 V, typ, clamps not added: 15.9 ohm
|   GND clamp passes 1 mA (typ) near -0.51 V on its own axis
|   POWER clamp passes 1 mA (typ) near -0.86 V on its own axis
|   rising waveform, R_fixture 50.000000, V_fixture 1.800000: 20-80 % time 489ps typ, 1.02ns min, 316ps max; typ from 0.414 V to 1.8 V
|   rising waveform, R_fixture 50.000000, V_fixture 0.0: 20-80 % time 31.5ns typ, 69.3ns min, 16.7ns max; typ from 0 V to 1.33 V
|   falling waveform, R_fixture 50.000000, V_fixture 1.800000: 20-80 % time 22.7ns typ, 57.7ns min, 11.6ns max; typ from 1.8 V to 0.414 V
|   falling waveform, R_fixture 50.000000, V_fixture 0.0: 20-80 % time 1.43ns typ, 2.11ns min, 1.03ns max; typ from 1.33 V to 0 V
[Pulldown]
|Voltage   I(typ)   I(min)   I(max)
-1.8V     -68.38mA   -32.32mA   -104.4mA
-960mV    -68.38mA   -32.32mA   -104.4mA
-780mV    -66.07mA   -32.32mA   -96.42mA
-660mV    -59.2mA    -32.31mA   -87.22mA
-540mV    -50.22mA   -28.51mA   -74.66mA
0V        0A         0A         0A
240mV     18.04mA    9.599mA    29.41mA
480mV     30.68mA    16.02mA    50.95mA
780mV     39.47mA    19.98mA    67.56mA
960mV     41.44mA    20.62mA    72.37mA
1.14V     41.98mA    20.78mA    74.01mA
3.6V      44.42mA    22.05mA    78.5mA
[Pullup]
|Voltage   I(typ)   I(min)   I(max)
-1.8V     37.47mA    19.74mA    56.72mA
-540mV    37.47mA    19.74mA    56.72mA
-480mV    37.47mA    19.74mA    53.05mA
-360mV    28.94mA    18.47mA    39.74mA
0V        630fA      250pA      0A
300mV     -18.63mA   -11.6mA    -27.18mA
600mV     -31.41mA   -19.24mA   -46.67mA
780mV     -36.41mA   -22mA      -54.88mA
960mV     -39.54mA   -23.52mA   -60.64mA
1.2V      -41.44mA   -24.28mA   -64.93mA
1.56V     -42.42mA   -24.69mA   -67.24mA
3.6V      -44.3mA    -26mA      -70.5mA
[GND_clamp]
|Voltage   I(typ)   I(min)   I(max)
-1.8V     -9.908A    -9.683A    -9.994A
-1.2V     -3.383A    -4.084A    -2.934A
-1.16V    -2.841A    -3.655A    -2.294A
-1.12V    -2.299A    -3.226A    -1.656A
-1.04V    -1.218A    -2.369A    -414.2mA
-1V       -684.7mA   -1.941A    -119.2mA
-960mV    -257.2mA   -1.514A    -45.66mA
-920mV    -87.03mA   -1.089A    -28.93mA
-840mV    -19.35mA   -312.8mA   -18.96mA
-800mV    -13.55mA   -132.4mA   -15.49mA
-720mV    -8.042mA   -25.66mA   -9.49mA
1.8V      0A         13.64nA    0A
[POWER_clamp]
|Voltage   I(typ)   I(min)   I(max)
-1.8V     470.9mA    433.7mA    554.6mA
-1.14V    95.28mA    122.7mA    82.88mA
-1.12V    85mA       114mA      70.34mA
-1.06V    55.55mA    88.43mA    35.73mA
-1.04V    46.38mA    80.17mA    25.83mA
-1V       29.54mA    64.14mA    10.37mA
-940mV    10.43mA    41.88mA    1.177mA
-900mV    3.66mA     28.79mA    250.5uA
-840mV    527.2uA    13.26mA    95.16uA
-800mV    153.8uA    6.55mA     88.66uA
-740mV    59.96uA    1.741mA    70.47uA
0V        0A         18.18nA    0A
[Ramp]
| variable   typ   min   max
dV/dt_r  0.79756/31.47430n   0.58780/69.16616n   0.97651/16.62743n
dV/dt_f  0.83131/22.61044n   0.56469/57.68765n   1.02742/11.61294n
R_load = 50.000000
[Rising Waveform]
R_fixture= 50.000000
V_fixture= 1.800000
V_fixture_min= 1.600000
V_fixture_max= 2.000000
|time   V(typ)   V(min)   V(max)
0s        414.5mV    657.5mV    287.6mV
2.482ns   413.9mV    657.6mV    391.2mV
2.723ns   412.9mV    657.6mV    689.7mV
3.083ns   423mV      657.6mV    1.799V
3.483ns   490.4mV    657.6mV    1.979V
3.884ns   718.3mV    657.3mV    1.994V
4.444ns   1.626V     655.7mV    1.998V
4.925ns   1.78V      657.4mV    1.999V
7.888ns   1.8V       1.582V     2V
19.94ns   1.8V       1.6V       2V
[Rising Waveform]
R_fixture= 50.000000
V_fixture= 0.0
V_fixture_min= 0.0
V_fixture_max= 0.0
|time   V(typ)   V(min)   V(max)
0s        425uV      507.6uV    388.2uV
9.61ns    1.827mV    803uV      6.813mV
14.41ns   3.557mV    1.507mV    126.6mV
24.82ns   93.1mV     2.926mV    720.2mV
36.84ns   384.1mV    25.71mV    1.364V
56.06ns   902.2mV    150mV      1.574V
83.28ns   1.234V     415.9mV    1.619V
121.7ns   1.311V     735.4mV    1.627V
157ns     1.325V     882.9mV    1.628V
398.8ns   1.33V      980.7mV    1.628V
[Falling Waveform]
R_fixture= 50.000000
V_fixture= 1.800000
V_fixture_min= 1.600000
V_fixture_max= 2.000000
|time   V(typ)   V(min)   V(max)
0s        1.8V       1.6V       2V
16.02ns   1.8V       1.6V       1.919V
20.82ns   1.793V     1.6V       1.637V
32.83ns   1.627V     1.597V     593.3mV
48.85ns   1.041V     1.547V     358.6mV
58.46ns   705.2mV    1.481V     327.2mV
71.27ns   556.1mV    1.358V     308.1mV
110.5ns   449.1mV    921.9mV    290.8mV
146.5ns   426mV      770.1mV    288.3mV
398.8ns   414.5mV    657.5mV    287.6mV
[Falling Waveform]
R_fixture= 50.000000
V_fixture= 0.0
V_fixture_min= 0.0
V_fixture_max= 0.0
|time   V(typ)   V(min)   V(max)
0s        1.33V      980.7mV    1.628V
1.562ns   1.33V      980.7mV    1.631V
2.002ns   1.333V     980.7mV    1.531V
2.763ns   1.257V     980.5mV    855.8mV
3.323ns   964.5mV    987mV      351.7mV
4.164ns   451.2mV    929.2mV    26.29mV
5.526ns   36.35mV    484.4mV    3.16mV
6.727ns   2.941mV    209.8mV    2.033mV
8.168ns   1.002mV    38.04mV    1.813mV
19.94ns   425uV      507.6uV    388.2uV
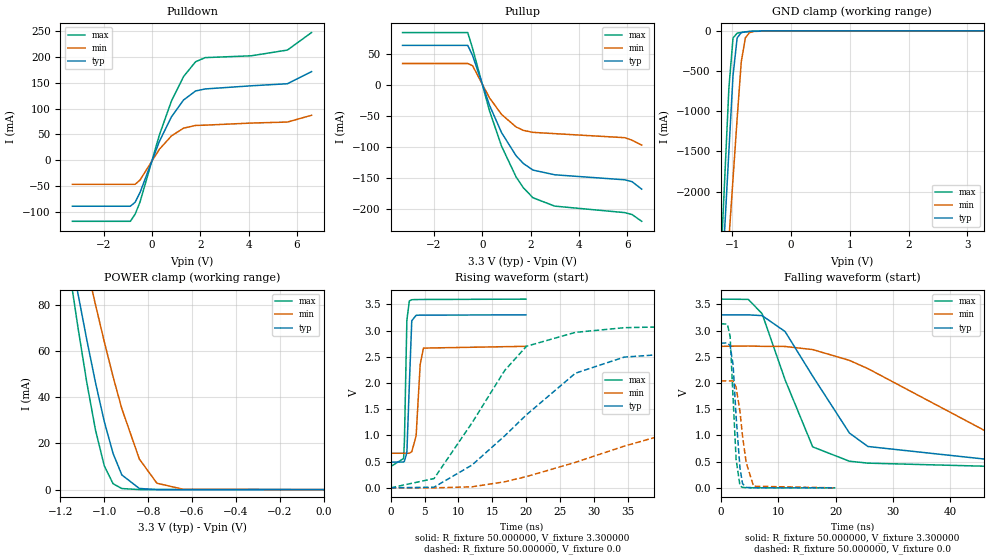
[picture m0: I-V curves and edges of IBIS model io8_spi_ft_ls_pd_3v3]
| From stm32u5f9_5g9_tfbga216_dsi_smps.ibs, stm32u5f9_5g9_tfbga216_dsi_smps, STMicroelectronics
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|   Model io8_spi_ft_ls_pd_3v3
[Model]  io8_spi_ft_ls_pd_3v3
Model_type I/O
Polarity   Non-Inverting
Enable   Active-Low
Vinl =   0.990000V
Vinh =   2.310000V
Vmeas =  1.650000V
Cref =   50.000000pF
Rref =   100.000000M
Vref =   0.0V
C_comp   3.495300pF   3.468500pF   3.534700pF
[Temperature Range]   25.000000   0.140000k   -40.000000
[Pullup Reference]   3.300000V   2.700000V   3.600000V
[Pulldown Reference]   0.0V   0.0V   0.0V
[POWER Clamp Reference]   3.300000V   2.700000V   3.600000V
[GND Clamp Reference]   0.0V   0.0V   0.0V
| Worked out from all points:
|   slope of the pulldown table from 0 to 0.495 V, typ, clamps not added: 8.73 ohm
|   slope of the pullup table from 0 to 0.495 V, typ, clamps not added: 9.64 ohm
|   GND clamp passes 1 mA (typ) near -0.50 V on its own axis
|   POWER clamp passes 1 mA (typ) near -0.85 V on its own axis
|   rising waveform, R_fixture 50.000000, V_fixture 3.300000: 20-80 % time 328ps typ, 506ps min, 284ps max; typ from 0.49 V to 3.3 V
|   rising waveform, R_fixture 50.000000, V_fixture 0.0: 20-80 % time 14.4ns typ, 31.3ns min, 9.34ns max; typ from 0 V to 2.76 V
|   falling waveform, R_fixture 50.000000, V_fixture 3.300000: 20-80 % time 9.55ns typ, 21.1ns min, 6.28ns max; typ from 3.3 V to 0.49 V
|   falling waveform, R_fixture 50.000000, V_fixture 0.0: 20-80 % time 949ps typ, 1.4ns min, 771ps max; typ from 2.76 V to 0 V
[Pulldown]
|Voltage   I(typ)   I(min)   I(max)
-3.3V     -89.72mA   -47.06mA   -119mA
-900mV    -89.72mA   -47.06mA   -119mA
-700mV    -81.75mA   -47.06mA   -104.8mA
-500mV    -62.92mA   -38.71mA   -81.44mA
300mV     36.2mA     21.01mA    48.7mA
800mV     84.06mA    46.96mA    114.8mA
1.3V      116.7mA    62.08mA    162.3mA
1.8V      134.4mA    67.38mA    191.2mA
2.2V      138.3mA    67.91mA    199.2mA
4.1V      144.4mA    71.97mA    202.7mA
5.6V      148.4mA    73.93mA    213.9mA
6.6V      171.9mA    87.1mA     247.9mA
[Pullup]
|Voltage   I(typ)   I(min)   I(max)
-3.3V     64.06mA    34.74mA    84.71mA
-600mV    64.06mA    34.74mA    84.71mA
-400mV    47.78mA    31.25mA    59.06mA
300mV     -32.62mA   -20.62mA   -41.63mA
800mV     -76.87mA   -47.45mA   -98.74mA
1.4V      -114.1mA   -67.68mA   -148.3mA
1.7V      -126.6mA   -73.14mA   -165.7mA
2.1V      -137.3mA   -76.42mA   -182mA
3V        -144.9mA   -78.48mA   -195.5mA
5.9V      -153mA     -85mA      -206mA
6.2V      -156mA     -89mA      -209mA
6.6V      -168mA     -97mA      -220mA
[GND_clamp]
|Voltage   I(typ)   I(min)   I(max)
-3.3V     -9.098A    -9.372A    -9.671A
-1.2V     -3.386A    -4.091A    -2.933A
-1.13V    -2.437A    -3.34A     -1.815A
-1.06V    -1.49A     -2.588A    -705.6mA
-990mV    -555.7mA   -1.839A    -89.05mA
-920mV    -88.14mA   -1.093A    -28.79mA
-850mV    -22.36mA   -387.4mA   -19.86mA
-780mV    -12.13mA   -88.01mA   -13.89mA
-710mV    -7.72mA    -22.53mA   -8.86mA
-640mV    -4.556mA   -7.872mA   -4.884mA
-360mV    -39.69uA   -179.8uA   -19.45uA
3.28V     83.52uA    56.87uA    102.4uA
[POWER_clamp]
|Voltage   I(typ)   I(min)   I(max)
-3.28V    1.355A     1.167A     1.664A
-1.16V    105.7mA    131.6mA    95.69mA
-1.12V    84.97mA    114mA      70.27mA
-1.08V    65.05mA    96.83mA    46.54mA
-1.04V    46.34mA    80.15mA    25.76mA
-1V       29.51mA    64.13mA    10.3mA
-960mV    15.69mA    48.99mA    2.571mA
-920mV    6.373mA    35.1mA     455.6uA
-840mV    490.7uA    13.24mA    11.36uA
-760mV    27.33uA    2.767mA    279.2nA
-640mV    348nA      134.1uA    17.42nA
0V        0A         19.95nA    0A
[Ramp]
| variable   typ   min   max
dV/dt_r  1.65672/14.38758n   1.22424/31.21263n   1.87812/9.32041n
dV/dt_f  1.68576/9.54161n   1.22390/21.05775n   1.91752/6.24879n
R_load = 50.000000
[Rising Waveform]
R_fixture= 50.000000
V_fixture= 3.300000
V_fixture_min= 2.700000
V_fixture_max= 3.600000
|time   V(typ)   V(min)   V(max)
0s        489.8mV    659.6mV    403.4mV
1.922ns   492.7mV    659.6mV    559.8mV
2.042ns   507.2mV    659.5mV    899.3mV
2.402ns   672.3mV    659.1mV    3.196V
2.763ns   1.963V     659.5mV    3.564V
3.123ns   3.187V     689.2mV    3.588V
3.764ns   3.29V      989.9mV    3.591V
4.364ns   3.294V     2.355V     3.592V
4.845ns   3.294V     2.665V     3.592V
19.94ns   3.299V     2.699V     3.599V
[Rising Waveform]
R_fixture= 50.000000
V_fixture= 0.0
V_fixture_min= 0.0
V_fixture_max= 0.0
|time   V(typ)   V(min)   V(max)
0s        15.39nV    112.3nV    48.72nV
6.406ns   12.13mV    -744.8uV   176.8mV
12.01ns   435.5mV    18.99mV    1.241V
16.82ns   991.2mV    115.9mV    2.239V
20.02ns   1.393V     213.9mV    2.7V
27.23ns   2.186V     485.8mV    2.965V
34.43ns   2.493V     795.3mV    3.054V
58.46ns   2.713V     1.674V     3.121V
92.09ns   2.755V     1.954V     3.13V
398.8ns   2.761V     2.04V      3.13V
[Falling Waveform]
R_fixture= 50.000000
V_fixture= 3.300000
V_fixture_min= 2.700000
V_fixture_max= 3.600000
|time   V(typ)   V(min)   V(max)
0s        3.299V     2.699V     3.599V
4.805ns   3.299V     2.705V     3.594V
7.207ns   3.285V     2.699V     3.322V
11.21ns   2.981V     2.696V     2.061V
16.02ns   2.13V      2.637V     781.5mV
22.42ns   1.045V     2.431V     508.1mV
25.63ns   788.8mV    2.274V     471.5mV
46.45ns   542.9mV    1.065V     411.3mV
71.27ns   502.4mV    782mV      404.5mV
398.8ns   489.8mV    659.6mV    403.4mV
[Falling Waveform]
R_fixture= 50.000000
V_fixture= 0.0
V_fixture_min= 0.0
V_fixture_max= 0.0
|time   V(typ)   V(min)   V(max)
0s        2.761V     2.04V      3.13V
1.161ns   2.763V     2.04V      3.123V
1.642ns   2.711V     2.04V      2.888V
2.162ns   2.341V     2.041V     1.701V
2.683ns   1.361V     1.92V      544.3mV
3.363ns   369mV      1.453V     38.26mV
3.804ns   81.7mV     983.1mV    9.098mV
4.444ns   8.85mV     479.8mV    2.956mV
5.726ns   1.42mV     30.85mV    1.813mV
19.94ns   15.39nV    112.3nV    48.72nV
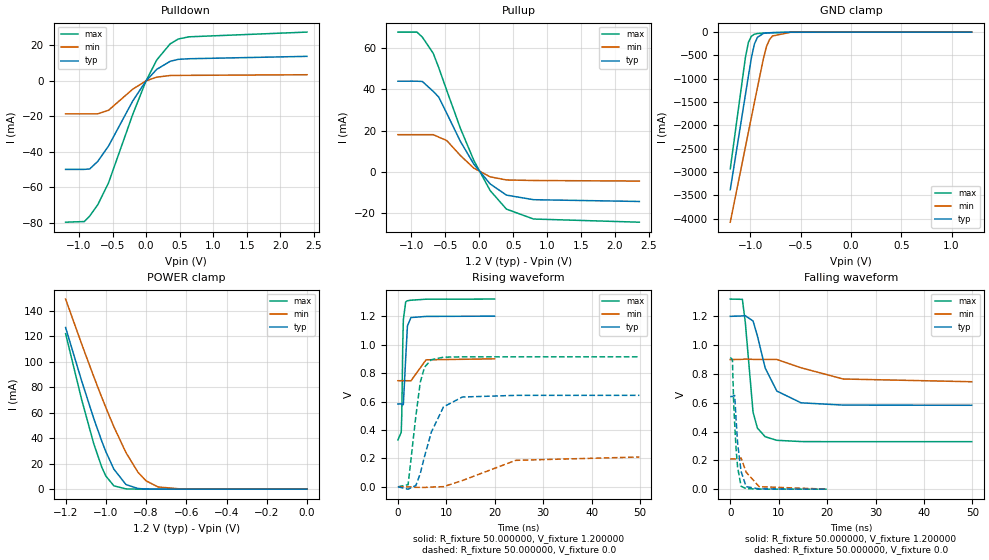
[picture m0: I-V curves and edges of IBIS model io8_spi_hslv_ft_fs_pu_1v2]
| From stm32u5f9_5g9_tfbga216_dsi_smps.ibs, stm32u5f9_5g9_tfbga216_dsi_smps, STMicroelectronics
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|   Model io8_spi_hslv_ft_fs_pu_1v2
[Model]  io8_spi_hslv_ft_fs_pu_1v2
Model_type I/O
Polarity   Non-Inverting
Enable   Active-Low
Vinl =   0.360000V
Vinh =   0.840000V
Vmeas =  0.600000V
Cref =   50.000000pF
Rref =   100.000000M
Vref =   0.0V
C_comp   3.133100pF   3.070300pF   3.178200pF
[Temperature Range]   25.000000   0.140000k   -40.000000
[Pullup Reference]   1.200000V   0.900000V   1.320000V
[Pulldown Reference]   0.0V   0.0V   0.0V
[POWER Clamp Reference]   1.200000V   0.900000V   1.320000V
[GND Clamp Reference]   0.0V   0.0V   0.0V
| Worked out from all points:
|   slope of the pulldown table from 0 to 0.18 V, typ, clamps not added: 25.4 ohm
|   slope of the pullup table from 0 to 0.18 V, typ, clamps not added: 27.8 ohm
|   GND clamp passes 1 mA (typ) near -0.51 V on its own axis
|   POWER clamp passes 1 mA (typ) near -0.86 V on its own axis
|   rising waveform, R_fixture 50.000000, V_fixture 1.200000: 20-80 % time 443ps typ, 1.04ns min, 265ps max; typ from 0.583 V to 1.2 V
|   rising waveform, R_fixture 50.000000, V_fixture 0.0: 20-80 % time 3.6ns typ, 8.61ns min, 1.83ns max; typ from 0 V to 0.643 V
|   falling waveform, R_fixture 50.000000, V_fixture 1.200000: 20-80 % time 3.56ns typ, 7.7ns min, 1.53ns max; typ from 1.2 V to 0.583 V
|   falling waveform, R_fixture 50.000000, V_fixture 0.0: 20-80 % time 1.05ns typ, 1.78ns min, 829ps max; typ from 0.643 V to 0 V
[Pulldown]
|Voltage   I(typ)   I(min)   I(max)
-1.2V     -49.85mA   -18.57mA   -79.56mA
-920mV    -49.85mA   -18.57mA   -79.19mA
-840mV    -49.59mA   -18.57mA   -76.08mA
-720mV    -45.32mA   -18.57mA   -69.73mA
-560mV    -36.71mA   -16.58mA   -57.44mA
-200mV    -11.43mA   -4.74mA    -19.03mA
0V        0A         0A         0A
160mV     6.476mA    2.075mA    11.78mA
360mV     10.99mA    2.989mA    20.81mA
480mV     12.07mA    3.053mA    23.52mA
640mV     12.42mA    3.074mA    24.76mA
2.4V      13.77mA    3.423mA    27.42mA
[Pullup]
|Voltage   I(typ)   I(min)   I(max)
-1.2V     43.99mA    18.03mA    67.83mA
-920mV    43.99mA    18.03mA    67.83mA
-840mV    43.85mA    18.03mA    65.37mA
-680mV    39.06mA    18.03mA    57.57mA
-600mV    36.35mA    16.87mA    50.72mA
-480mV    28.4mA     15.18mA    39.49mA
-280mV    14.84mA    7.942mA    21.22mA
-80mV     3.667mA    1.75mA     5.47mA
160mV     -5.889mA   -2.43mA    -9.115mA
400mV     -11.31mA   -3.958mA   -18.11mA
800mV     -13.54mA   -4.214mA   -22.92mA
2.36V     -14.4mA    -4.5mA     -24.46mA
[GND_clamp]
|Voltage   I(typ)   I(min)   I(max)
-1.2V     -3.379A    -4.076A    -2.932A
-1.05V    -1.35A     -2.47A     -550.7mA
-1.02V    -947.8mA   -2.149A    -221.5mA
-990mV    -552.4mA   -1.829A    -88.44mA
-960mV    -255.3mA   -1.51A     -44.87mA
-930mV    -111.8mA   -1.191A    -30.68mA
-870mV    -28.35mA   -564.6mA   -21.34mA
-840mV    -18.65mA   -309.5mA   -18.49mA
-810mV    -14.07mA   -161.6mA   -15.92mA
-780mV    -11.37mA   -83.33mA   -13.53mA
-600mV    -3.009mA   -4.321mA   -3.091mA
1.2V      0A         13.65nA    0A
[POWER_clamp]
|Voltage   I(typ)   I(min)   I(max)
-1.2V     127mA      149.4mA    122.2mA
-1.12V    84.98mA    114mA      70.29mA
-1.06V    55.52mA    88.42mA    35.69mA
-1.02V    37.64mA    72.04mA    17.19mA
-1V       29.52mA    64.13mA    10.33mA
-960mV    15.7mA     48.99mA    2.596mA
-900mV    3.636mA    28.77mA    207.8uA
-840mV    502.9uA    13.24mA    43.46uA
-800mV    129uA      6.535mA    43.46uA
-740mV    26.25uA    1.726mA    43.46uA
-620mV    25.09uA    82.33uA    35.76uA
0V        0A         17.36nA    0A
[Ramp]
| variable   typ   min   max
dV/dt_r  0.38568/3.59511n   0.12561/8.59825n   0.54818/1.82350n
dV/dt_f  0.37036/3.55786n   92.28000m/7.71458n  0.59402/1.52931n
R_load = 50.000000
[Rising Waveform]
R_fixture= 50.000000
V_fixture= 1.200000
V_fixture_min= 0.900000
V_fixture_max= 1.320000
|time   V(typ)   V(min)   V(max)
0s        582.7mV    746.1mV    330mV
680.7ps   582.7mV    746.1mV    383.1mV
800.8ps   581.2mV    746.1mV    514.5mV
1.001ns   575.2mV    746.1mV    1.005V
1.121ns   580.7mV    746.1mV    1.175V
1.602ns   903.1mV    746.1mV    1.3V
1.962ns   1.131V     746.2mV    1.308V
2.683ns   1.19V      745.4mV    1.312V
5.806ns   1.198V     893mV      1.319V
19.94ns   1.2V       900mV      1.32V
[Rising Waveform]
R_fixture= 50.000000
V_fixture= 0.0
V_fixture_min= 0.0
V_fixture_max= 0.0
|time   V(typ)   V(min)   V(max)
0s        432.3uV    497uV      359.7uV
2.102ns   -16mV      501.3uV    15.65mV
3.704ns   9.759mV    -3.373mV   498.7mV
4.605ns   92.69mV    -3.191mV   734.2mV
5.506ns   215.7mV    -3.967mV   842.4mV
6.907ns   385.5mV    -1.102mV   893.6mV
9.409ns   562.3mV    1.571mV    911.5mV
13.31ns   631.6mV    44.73mV    914mV
24.32ns   643.2mV    186.6mV    914.1mV
49.85ns   643.4mV    210mV      914.2mV
[Falling Waveform]
R_fixture= 50.000000
V_fixture= 1.200000
V_fixture_min= 0.900000
V_fixture_max= 1.320000
|time   V(typ)   V(min)   V(max)
0s        1.2V       900mV      1.32V
2.503ns   1.203V     901.4mV    1.318V
3.103ns   1.204V     903.7mV    1.159V
4.705ns   1.168V     901.3mV    534.4mV
5.606ns   1.064V     901.1mV    424.1mV
7.207ns   841.7mV    901mV      364.4mV
9.61ns    681.6mV    900.8mV    339.6mV
14.61ns   599.8mV    843mV      330.8mV
23.32ns   583.9mV    765.1mV    330mV
49.85ns   582.7mV    746.1mV    330mV
[Falling Waveform]
R_fixture= 50.000000
V_fixture= 0.0
V_fixture_min= 0.0
V_fixture_max= 0.0
|time   V(typ)   V(min)   V(max)
0s        643.4mV    210mV      914.2mV
440.4ps   643.2mV    210mV      899.9mV
720.7ps   649.2mV    210.1mV    581.3mV
920.9ps   650.7mV    210.1mV    449.2mV
1.201ns   481.4mV    210.1mV    279.7mV
1.522ns   318.7mV    209.9mV    150.9mV
2.242ns   122.2mV    216.9mV    20.44mV
3.283ns   17.49mV    118.1mV    4.132mV
5.966ns   2.312mV    17.62mV    824.3uV
19.94ns   432.3uV    497uV      359.7uV
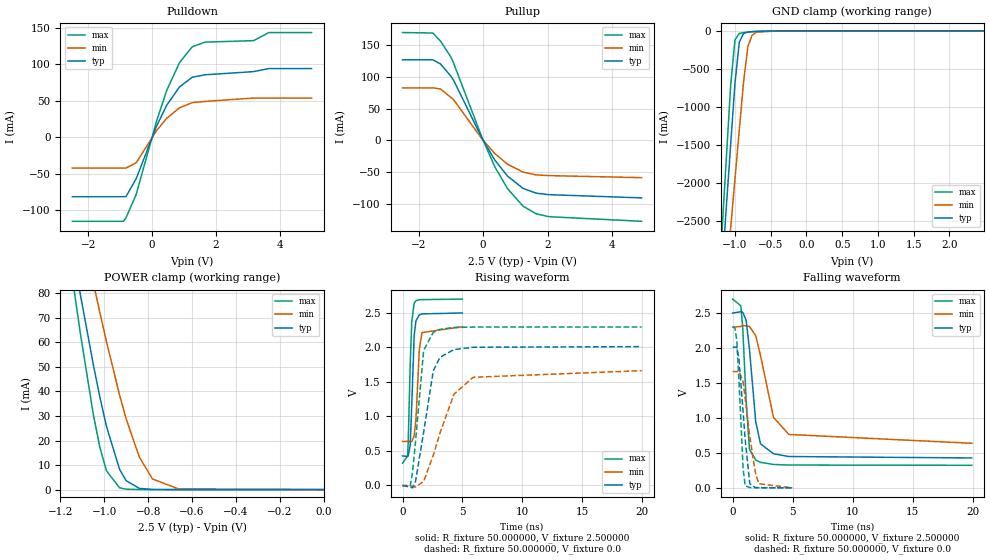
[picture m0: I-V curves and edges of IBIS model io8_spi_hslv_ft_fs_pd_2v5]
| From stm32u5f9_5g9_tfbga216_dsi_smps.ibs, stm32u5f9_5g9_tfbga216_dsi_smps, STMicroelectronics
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|   Model io8_spi_hslv_ft_fs_pd_2v5
[Model]  io8_spi_hslv_ft_fs_pd_2v5
Model_type I/O
Polarity   Non-Inverting
Enable   Active-Low
Vinl =   0.750000V
Vinh =   1.750000V
Vmeas =  1.250000V
Cref =   50.000000pF
Rref =   100.000000M
Vref =   0.0V
C_comp   3.438200pF   3.436700pF   3.473300pF
[Temperature Range]   25.000000   0.140000k   -40.000000
[Pullup Reference]   2.500000V   2.300000V   2.700000V
[Pulldown Reference]   0.0V   0.0V   0.0V
[POWER Clamp Reference]   2.500000V   2.300000V   2.700000V
[GND Clamp Reference]   0.0V   0.0V   0.0V
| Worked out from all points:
|   slope of the pulldown table from 0 to 0.375 V, typ, clamps not added: 10.1 ohm
|   slope of the pullup table from 0 to 0.375 V, typ, clamps not added: 11.7 ohm
|   GND clamp passes 1 mA (typ) near -0.50 V on its own axis
|   POWER clamp passes 1 mA (typ) near -0.86 V on its own axis
|   rising waveform, R_fixture 50.000000, V_fixture 2.500000: 20-80 % time 229ps typ, 276ps min, 225ps max; typ from 0.428 V to 2.5 V
|   rising waveform, R_fixture 50.000000, V_fixture 0.0: 20-80 % time 1.04ns typ, 1.94ns min, 684ps max; typ from 0 V to 2.01 V
|   falling waveform, R_fixture 50.000000, V_fixture 2.500000: 20-80 % time 646ps typ, 1.26ns min, 408ps max; typ from 2.5 V to 0.428 V
|   falling waveform, R_fixture 50.000000, V_fixture 0.0: 20-80 % time 547ps typ, 764ps min, 383ps max; typ from 2.01 V to 0 V
[Pulldown]
|Voltage   I(typ)   I(min)   I(max)
-2.5V     -81.62mA   -42.31mA   -115.3mA
-900mV    -81.62mA   -42.31mA   -115.3mA
-820mV    -81.42mA   -42.31mA   -110.6mA
-500mV    -56.95mA   -35.08mA   -78.57mA
140mV     15.18mA    9.02mA     22.02mA
460mV     44mA       25.98mA    64.37mA
860mV     68.91mA    40.27mA    102.2mA
1.26V     82.21mA    47.42mA    124mA
1.66V     85.53mA    48.99mA    130.3mA
3.18V     89.84mA    53.65mA    132.3mA
3.66V     94.05mA    53.65mA    143.4mA
5V        94.05mA    53.65mA    143.4mA
[Pullup]
|Voltage   I(typ)   I(min)   I(max)
-2.5V     127.4mA    82.99mA    170.4mA
-1.56V    127.4mA    82.99mA    169.7mA
-1.32V    120.7mA    81.18mA    156.8mA
-1V       101.4mA    67.88mA    131.8mA
-920mV    95.46mA    64.48mA    122.7mA
-40mV     3.893mA    2.628mA    5.181mA
360mV     -30.97mA   -20.78mA   -41.56mA
760mV     -56.64mA   -37.85mA   -76.55mA
1.24V     -75.99mA   -50.28mA   -104.1mA
1.64V     -83.42mA   -54.54mA   -116.1mA
2.04V     -85.88mA   -55.77mA   -120.7mA
4.92V     -91mA      -59mA      -128mA
[GND_clamp]
|Voltage   I(typ)   I(min)   I(max)
-2.5V     -9.641A    -9.693A    -9.352A
-1.18V    -3.114A    -3.874A    -2.614A
-1.12V    -2.301A    -3.23A     -1.656A
-1.06V    -1.489A    -2.587A    -706.2mA
-1V       -685.8mA   -1.945A    -119.3mA
-940mV    -149.8mA   -1.304A    -34.74mA
-880mV    -35.55mA   -672.6mA   -23.08mA
-820mV    -16.2mA    -206.4mA   -17.29mA
-760mV    -10.59mA   -57.56mA   -12.42mA
-700mV    -7.162mA   -18.75mA   -8.254mA
-400mV    -112.4uA   -385.2uA   -53.46uA
2.48V     63.1uA     48.03uA    77.39uA
[POWER_clamp]
|Voltage   I(typ)   I(min)   I(max)
-2.49V    881mA      773.1mA    1.07A
-1.14V    95.25mA    122.7mA    82.82mA
-1.11V    79.9mA     109.7mA    64.14mA
-1.05V    50.87mA    84.26mA    30.57mA
-1.02V    37.63mA    72.04mA    17.17mA
-990mV    25.71mA    60.25mA    7.621mA
-930mV    8.217mA    38.43mA    713.9uA
-900mV    3.624mA    28.77mA    182.8uA
-840mV    490.7uA    13.24mA    11.35uA
-780mV    56.55uA    4.324mA    699nA
-660mV    716.7nA    226uA      9.786nA
0V        0A         19.53nA    0A
[Ramp]
| variable   typ   min   max
dV/dt_r  1.20630/1.04108n   0.99750/1.93989n   1.37748/0.68362n
dV/dt_f  1.24320/0.64470n   0.99721/1.25459n   1.42604/0.40595n
R_load = 50.000000
[Rising Waveform]
R_fixture= 50.000000
V_fixture= 2.500000
V_fixture_min= 2.300000
V_fixture_max= 2.700000
|time   V(typ)   V(min)   V(max)
0s        427.5mV    637.3mV    322.7mV
420.4ps   421.1mV    637.4mV    425.1mV
470.5ps   429mV      637.3mV    607.2mV
640.6ps   582.6mV    633.5mV    1.752V
770.8ps   1.168V     634.5mV    2.375V
971ps     2.171V     721.1mV    2.641V
1.121ns   2.385V     962.2mV    2.677V
1.401ns   2.472V     1.972V     2.689V
1.622ns   2.485V     2.215V     2.692V
4.985ns   2.499V     2.299V     2.699V
[Rising Waveform]
R_fixture= 50.000000
V_fixture= 0.0
V_fixture_min= 0.0
V_fixture_max= 0.0
|time   V(typ)   V(min)   V(max)
0s        -32.76uV   -5.739uV   52.49uV
640.6ps   -24.2mV    -1.11mV    -17.07mV
840.8ps   -34.45mV   -13.73mV   201.9mV
1.081ns   55.68mV    -21.74mV   633.3mV
1.762ns   773.1mV    58.99mV    1.958V
2.563ns   1.66V      438.2mV    2.218V
3.123ns   1.856V     758.6mV    2.261V
4.284ns   1.968V     1.321V     2.289V
5.886ns   2.002V     1.567V     2.294V
19.94ns   2.011V     1.663V     2.295V
[Falling Waveform]
R_fixture= 50.000000
V_fixture= 2.500000
V_fixture_min= 2.300000
V_fixture_max= 2.700000
|time   V(typ)   V(min)   V(max)
0s        2.499V     2.299V     2.699V
680.7ps   2.519V     2.308V     2.604V
840.8ps   2.511V     2.321V     2.289V
1.121ns   2.397V     2.316V     1.263V
1.401ns   1.984V     2.308V     553.1mV
1.922ns   948.8mV    2.177V     397.5mV
2.322ns   630.4mV    1.893V     364.8mV
3.403ns   487.4mV    1.009V     334.6mV
4.685ns   448.2mV    763.8mV    326.1mV
19.94ns   427.5mV    637.3mV    322.7mV
[Falling Waveform]
R_fixture= 50.000000
V_fixture= 0.0
V_fixture_min= 0.0
V_fixture_max= 0.0
|time   V(typ)   V(min)   V(max)
0s        2.011V     1.663V     2.295V
190.2ps   2.011V     1.663V     2.293V
340.3ps   2.016V     1.663V     2.111V
530.5ps   1.833V     1.665V     1.522V
870.9ps   1.089V     1.524V     277.9mV
1.041ns   695.8mV    1.286V     30.52mV
1.431ns   59.3mV     726.6mV    3.894mV
1.892ns   4.667mV    219.2mV    1.992mV
2.172ns   2.826mV    59.9mV     1.569mV
4.985ns   -32.76uV   -5.739uV   52.49uV
